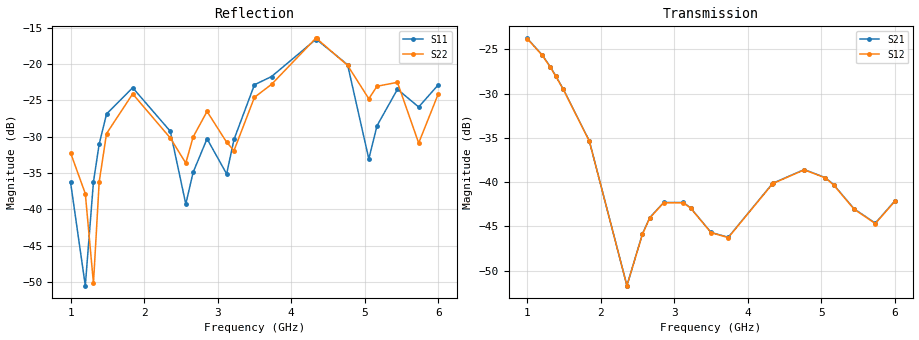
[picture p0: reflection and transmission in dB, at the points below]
!Agilent Technologies,E8364B,MY43040528,A.07.50.67
!Agilent E8364B: A.07.50.67
!Date: Sunday, March 01, 2026 22:11:33
!Correction: S11(Full 2 Port(1,2))
!S21(Full 2 Port(1,2))
!S12(Full 2 Port(1,2))
!S22(Full 2 Port(1,2))
!S2P File: Measurements: S11, S21, S12, S22:
# Hz S  dB  R 50
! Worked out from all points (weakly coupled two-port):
!   451 points, 1 GHz to 6 GHz, reference 50 ohm
!   highest |S21| = -23.75 dB at 1 GHz (marker M1); lowest = -51.7 dB at 2.356 GHz (marker M2)
!   lowest |S11| = -50.5 dB at 1.2 GHz (marker M3), VSWR 1.01, Z = 50.1 - j0.26 ohm
!   |S11| at or under -10 dB: start of sweep to end of sweep
!   |S22| runs from -50.2 to -16.4 dB; largest |S21 - S12| = 0.00028
!   S11 on the Smith chart (normalised r, x): 1 GHz: 1.03, +0.01; 4.333 GHz: 1.23, -0.24; 6 GHz: 0.98, -0.14
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1e9  -36.29 15.8  -23.75 154.9  -23.79 154.9  -32.23 -14.4
1.2e9  -50.53 -60.8  -25.60 40.8  -25.63 40.8  -37.83 -32.1
1.311111e9  -36.21 -149.5  -26.93 -21.9  -26.97 -21.8  -50.21 -155.7
1.388889e9  -31.02 -172.2  -28.01 -65.1  -28.04 -65.0  -36.24 118.9
1.488889e9  -26.86 160.1  -29.48 -119.6  -29.50 -119.6  -29.56 84.0
1.844444e9  -23.24 83.1  -35.34 51.0  -35.37 51.0  -24.09 -9.3
2.355556e9  -29.24 11.4  -51.68 -148.9  -51.69 -149.0  -30.17 -92.4
2.566667e9  -39.28 34.0  -45.83 151.9  -45.88 151.9  -33.63 -68.2
2.666667e9  -34.90 70.7  -43.99 103.7  -44.03 103.8  -30.03 -64.1
2.855556e9  -30.28 51.3  -42.29 6.7  -42.32 6.7  -26.51 -98.9
3.122222e9  -35.13 68.6  -42.29 -132.7  -42.32 -132.8  -30.76 -138.4
3.222222e9  -30.37 86.9  -42.91 176.1  -42.94 176.1  -31.91 -121.6
3.5e9  -22.84 54.9  -45.68 46.6  -45.70 46.7  -24.57 -132.5
3.733333e9  -21.70 31.2  -46.22 -44.2  -46.26 -44.1  -22.77 -158.7
4.333333e9  -16.60 -39.2  -40.17 28.8  -40.20 28.9  -16.44 113.7
4.344444e9  -16.59 -40.9  -40.10 22.9  -40.13 22.9  -16.45 111.5
4.766667e9  -20.07 -110.3  -38.57 148.2  -38.60 148.3  -20.16 36.1
5.055556e9  -33.06 -103.4  -39.49 -21.1  -39.52 -21.1  -24.77 33.9
5.166667e9  -28.49 -61.6  -40.28 -88.0  -40.32 -88.0  -23.04 30.3
5.444444e9  -23.46 -93.0  -43.01 95.2  -43.05 95.1  -22.50 -20.2
5.733333e9  -25.90 -96.3  -44.62 -113.5  -44.67 -113.4  -30.87 -25.8
6e9  -22.84 -94.8  -42.10 59.1  -42.14 59.0  -24.09 -21.0
